VERSION 5.7 ;
  NOWIREEXTENSIONATPIN ON ;
  DIVIDERCHAR "/" ;
  BUSBITCHARS "[]" ;
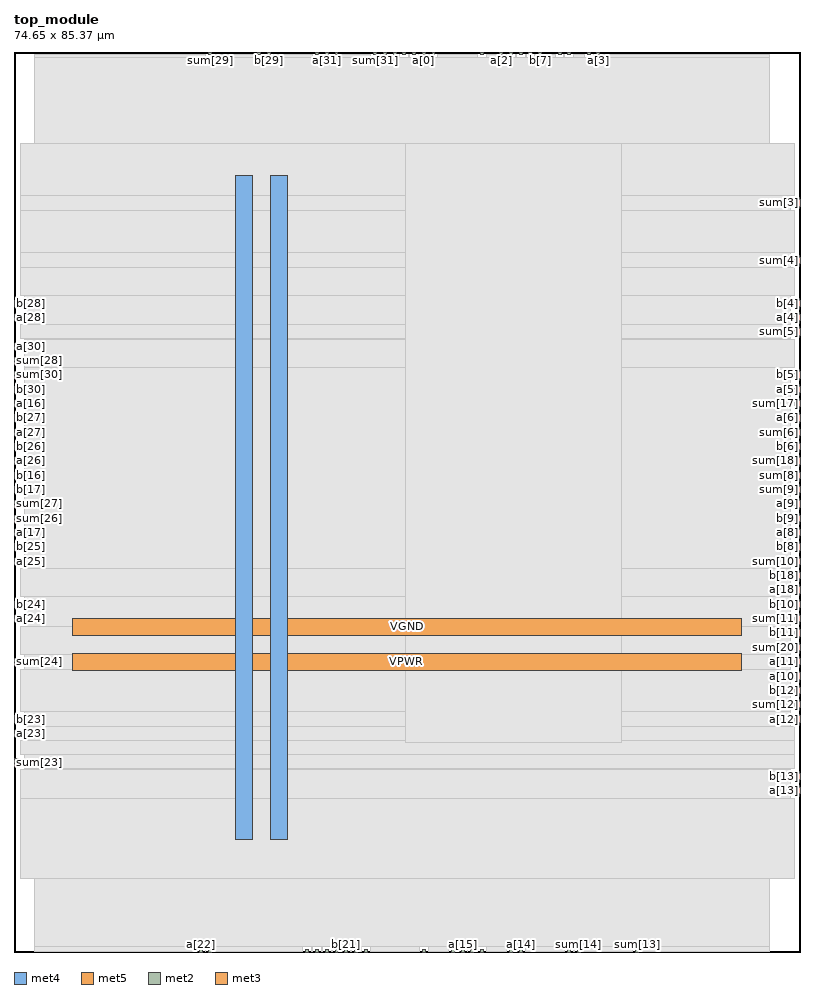
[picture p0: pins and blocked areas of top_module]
MACRO top_module
  CLASS BLOCK ;
  FOREIGN top_module ;
  ORIGIN 0.000 0.000 ;
  SIZE 74.650 BY 85.370 ;
  PIN VGND
    DIRECTION INOUT ;
    USE GROUND ;
    PORT
      LAYER met4 ;
        RECT 24.340 10.640 25.940 73.680 ;
    END
    PORT
      LAYER met5 ;
        RECT 5.520 30.030 69.000 31.630 ;
    END
  END VGND
  PIN VPWR
    DIRECTION INOUT ;
    USE POWER ;
    PORT
      LAYER met4 ;
        RECT 21.040 10.640 22.640 73.680 ;
    END
    PORT
      LAYER met5 ;
        RECT 5.520 26.730 69.000 28.330 ;
    END
  END VPWR
  PIN a[0]
    DIRECTION INPUT ;
    USE SIGNAL ;
    ANTENNAGATEAREA 0.213000 ;
    PORT
      LAYER met2 ;
        RECT 38.730 85.090 39.010 85.370 ;
    END
  END a[0]
  PIN a[10]
    DIRECTION INPUT ;
    USE SIGNAL ;
    ANTENNAGATEAREA 0.213000 ;
    PORT
      LAYER met3 ;
        RECT 74.050 25.880 74.650 26.480 ;
    END
  END a[10]
  PIN a[11]
    DIRECTION INPUT ;
    USE SIGNAL ;
    ANTENNAGATEAREA 0.213000 ;
    PORT
      LAYER met3 ;
        RECT 74.050 27.240 74.650 27.840 ;
    END
  END a[11]
  PIN a[12]
    DIRECTION INPUT ;
    USE SIGNAL ;
    ANTENNAGATEAREA 0.213000 ;
    PORT
      LAYER met3 ;
        RECT 74.050 21.800 74.650 22.400 ;
    END
  END a[12]
  PIN a[13]
    DIRECTION INPUT ;
    USE SIGNAL ;
    ANTENNAGATEAREA 0.213000 ;
    PORT
      LAYER met3 ;
        RECT 74.050 15.000 74.650 15.600 ;
    END
  END a[13]
  PIN a[14]
    DIRECTION INPUT ;
    USE SIGNAL ;
    ANTENNAGATEAREA 0.213000 ;
    PORT
      LAYER met2 ;
        RECT 47.930 0.000 48.210 0.280 ;
    END
  END a[14]
  PIN a[15]
    DIRECTION INPUT ;
    USE SIGNAL ;
    ANTENNAGATEAREA 0.213000 ;
    PORT
      LAYER met2 ;
        RECT 42.410 0.000 42.690 0.280 ;
    END
  END a[15]
  PIN a[16]
    DIRECTION INPUT ;
    USE SIGNAL ;
    ANTENNAGATEAREA 0.213000 ;
    PORT
      LAYER met3 ;
        RECT 0.000 51.720 0.600 52.320 ;
    END
  END a[16]
  PIN a[17]
    DIRECTION INPUT ;
    USE SIGNAL ;
    ANTENNAGATEAREA 0.213000 ;
    PORT
      LAYER met3 ;
        RECT 0.000 39.480 0.600 40.080 ;
    END
  END a[17]
  PIN a[18]
    DIRECTION INPUT ;
    USE SIGNAL ;
    ANTENNAGATEAREA 0.126000 ;
    PORT
      LAYER met3 ;
        RECT 74.050 34.040 74.650 34.640 ;
    END
  END a[18]
  PIN a[19]
    DIRECTION INPUT ;
    USE SIGNAL ;
    ANTENNAGATEAREA 0.213000 ;
    PORT
      LAYER met2 ;
        RECT 32.290 0.000 32.570 0.280 ;
    END
  END a[19]
  PIN a[1]
    DIRECTION INPUT ;
    USE SIGNAL ;
    ANTENNAGATEAREA 0.742500 ;
    PORT
      LAYER met2 ;
        RECT 35.050 85.090 35.330 85.370 ;
    END
  END a[1]
  PIN a[20]
    DIRECTION INPUT ;
    USE SIGNAL ;
    ANTENNAGATEAREA 0.213000 ;
    PORT
      LAYER met2 ;
        RECT 44.250 0.000 44.530 0.280 ;
    END
  END a[20]
  PIN a[21]
    DIRECTION INPUT ;
    USE SIGNAL ;
    ANTENNAGATEAREA 0.213000 ;
    PORT
      LAYER met2 ;
        RECT 30.450 0.000 30.730 0.280 ;
    END
  END a[21]
  PIN a[22]
    DIRECTION INPUT ;
    USE SIGNAL ;
    ANTENNAGATEAREA 0.213000 ;
    PORT
      LAYER met2 ;
        RECT 17.570 0.000 17.850 0.280 ;
    END
  END a[22]
  PIN a[23]
    DIRECTION INPUT ;
    USE SIGNAL ;
    ANTENNAGATEAREA 0.213000 ;
    PORT
      LAYER met3 ;
        RECT 0.000 20.440 0.600 21.040 ;
    END
  END a[23]
  PIN a[24]
    DIRECTION INPUT ;
    USE SIGNAL ;
    ANTENNAGATEAREA 0.213000 ;
    PORT
      LAYER met3 ;
        RECT 0.000 31.320 0.600 31.920 ;
    END
  END a[24]
  PIN a[25]
    DIRECTION INPUT ;
    USE SIGNAL ;
    ANTENNAGATEAREA 0.213000 ;
    PORT
      LAYER met3 ;
        RECT 0.000 36.760 0.600 37.360 ;
    END
  END a[25]
  PIN a[26]
    DIRECTION INPUT ;
    USE SIGNAL ;
    ANTENNAGATEAREA 0.213000 ;
    PORT
      LAYER met3 ;
        RECT 0.000 46.280 0.600 46.880 ;
    END
  END a[26]
  PIN a[27]
    DIRECTION INPUT ;
    USE SIGNAL ;
    ANTENNAGATEAREA 0.213000 ;
    PORT
      LAYER met3 ;
        RECT 0.000 49.000 0.600 49.600 ;
    END
  END a[27]
  PIN a[28]
    DIRECTION INPUT ;
    USE SIGNAL ;
    ANTENNAGATEAREA 0.213000 ;
    PORT
      LAYER met3 ;
        RECT 0.000 59.880 0.600 60.480 ;
    END
  END a[28]
  PIN a[29]
    DIRECTION INPUT ;
    USE SIGNAL ;
    ANTENNAGATEAREA 0.213000 ;
    PORT
      LAYER met2 ;
        RECT 23.090 85.090 23.370 85.370 ;
    END
  END a[29]
  PIN a[2]
    DIRECTION INPUT ;
    USE SIGNAL ;
    ANTENNAGATEAREA 0.213000 ;
    PORT
      LAYER met2 ;
        RECT 46.090 85.090 46.370 85.370 ;
    END
  END a[2]
  PIN a[30]
    DIRECTION INPUT ;
    USE SIGNAL ;
    ANTENNAGATEAREA 0.213000 ;
    PORT
      LAYER met3 ;
        RECT 0.000 57.160 0.600 57.760 ;
    END
  END a[30]
  PIN a[31]
    DIRECTION INPUT ;
    USE SIGNAL ;
    ANTENNAGATEAREA 0.213000 ;
    PORT
      LAYER met2 ;
        RECT 29.530 85.090 29.810 85.370 ;
    END
  END a[31]
  PIN a[3]
    DIRECTION INPUT ;
    USE SIGNAL ;
    ANTENNAGATEAREA 0.213000 ;
    PORT
      LAYER met2 ;
        RECT 55.290 85.090 55.570 85.370 ;
    END
  END a[3]
  PIN a[4]
    DIRECTION INPUT ;
    USE SIGNAL ;
    ANTENNAGATEAREA 0.213000 ;
    PORT
      LAYER met3 ;
        RECT 74.050 59.880 74.650 60.480 ;
    END
  END a[4]
  PIN a[5]
    DIRECTION INPUT ;
    USE SIGNAL ;
    ANTENNAGATEAREA 0.213000 ;
    PORT
      LAYER met3 ;
        RECT 74.050 53.080 74.650 53.680 ;
    END
  END a[5]
  PIN a[6]
    DIRECTION INPUT ;
    USE SIGNAL ;
    ANTENNAGATEAREA 0.213000 ;
    PORT
      LAYER met3 ;
        RECT 74.050 50.360 74.650 50.960 ;
    END
  END a[6]
  PIN a[7]
    DIRECTION INPUT ;
    USE SIGNAL ;
    ANTENNAGATEAREA 0.213000 ;
    PORT
      LAYER met2 ;
        RECT 48.850 85.090 49.130 85.370 ;
    END
  END a[7]
  PIN a[8]
    DIRECTION INPUT ;
    USE SIGNAL ;
    ANTENNAGATEAREA 0.213000 ;
    PORT
      LAYER met3 ;
        RECT 74.050 39.480 74.650 40.080 ;
    END
  END a[8]
  PIN a[9]
    DIRECTION INPUT ;
    USE SIGNAL ;
    ANTENNAGATEAREA 0.213000 ;
    PORT
      LAYER met3 ;
        RECT 74.050 42.200 74.650 42.800 ;
    END
  END a[9]
  PIN b[0]
    DIRECTION INPUT ;
    USE SIGNAL ;
    ANTENNAGATEAREA 0.495000 ;
    PORT
      LAYER met2 ;
        RECT 36.890 85.090 37.170 85.370 ;
    END
  END b[0]
  PIN b[10]
    DIRECTION INPUT ;
    USE SIGNAL ;
    ANTENNAGATEAREA 0.213000 ;
    PORT
      LAYER met3 ;
        RECT 74.050 32.680 74.650 33.280 ;
    END
  END b[10]
  PIN b[11]
    DIRECTION INPUT ;
    USE SIGNAL ;
    ANTENNAGATEAREA 0.213000 ;
    PORT
      LAYER met3 ;
        RECT 74.050 29.960 74.650 30.560 ;
    END
  END b[11]
  PIN b[12]
    DIRECTION INPUT ;
    USE SIGNAL ;
    ANTENNAGATEAREA 0.213000 ;
    PORT
      LAYER met3 ;
        RECT 74.050 24.520 74.650 25.120 ;
    END
  END b[12]
  PIN b[13]
    DIRECTION INPUT ;
    USE SIGNAL ;
    ANTENNAGATEAREA 0.213000 ;
    PORT
      LAYER met3 ;
        RECT 74.050 16.360 74.650 16.960 ;
    END
  END b[13]
  PIN b[14]
    DIRECTION INPUT ;
    USE SIGNAL ;
    ANTENNAGATEAREA 0.213000 ;
    PORT
      LAYER met2 ;
        RECT 47.010 0.000 47.290 0.280 ;
    END
  END b[14]
  PIN b[15]
    DIRECTION INPUT ;
    USE SIGNAL ;
    ANTENNAGATEAREA 0.213000 ;
    PORT
      LAYER met2 ;
        RECT 41.490 0.000 41.770 0.280 ;
    END
  END b[15]
  PIN b[16]
    DIRECTION INPUT ;
    USE SIGNAL ;
    ANTENNAGATEAREA 0.213000 ;
    PORT
      LAYER met3 ;
        RECT 0.000 44.920 0.600 45.520 ;
    END
  END b[16]
  PIN b[17]
    DIRECTION INPUT ;
    USE SIGNAL ;
    ANTENNAGATEAREA 0.213000 ;
    PORT
      LAYER met3 ;
        RECT 0.000 43.560 0.600 44.160 ;
    END
  END b[17]
  PIN b[18]
    DIRECTION INPUT ;
    USE SIGNAL ;
    ANTENNAGATEAREA 0.126000 ;
    PORT
      LAYER met3 ;
        RECT 74.050 35.400 74.650 36.000 ;
    END
  END b[18]
  PIN b[19]
    DIRECTION INPUT ;
    USE SIGNAL ;
    ANTENNAGATEAREA 0.213000 ;
    PORT
      LAYER met2 ;
        RECT 33.210 0.000 33.490 0.280 ;
    END
  END b[19]
  PIN b[1]
    DIRECTION INPUT ;
    USE SIGNAL ;
    ANTENNAGATEAREA 0.495000 ;
    PORT
      LAYER met2 ;
        RECT 35.970 85.090 36.250 85.370 ;
    END
  END b[1]
  PIN b[20]
    DIRECTION INPUT ;
    USE SIGNAL ;
    ANTENNAGATEAREA 0.213000 ;
    PORT
      LAYER met2 ;
        RECT 43.330 0.000 43.610 0.280 ;
    END
  END b[20]
  PIN b[21]
    DIRECTION INPUT ;
    USE SIGNAL ;
    ANTENNAGATEAREA 0.213000 ;
    PORT
      LAYER met2 ;
        RECT 31.370 0.000 31.650 0.280 ;
    END
  END b[21]
  PIN b[22]
    DIRECTION INPUT ;
    USE SIGNAL ;
    ANTENNAGATEAREA 0.213000 ;
    PORT
      LAYER met2 ;
        RECT 18.490 0.000 18.770 0.280 ;
    END
  END b[22]
  PIN b[23]
    DIRECTION INPUT ;
    USE SIGNAL ;
    ANTENNAGATEAREA 0.213000 ;
    PORT
      LAYER met3 ;
        RECT 0.000 21.800 0.600 22.400 ;
    END
  END b[23]
  PIN b[24]
    DIRECTION INPUT ;
    USE SIGNAL ;
    ANTENNAGATEAREA 0.213000 ;
    PORT
      LAYER met3 ;
        RECT 0.000 32.680 0.600 33.280 ;
    END
  END b[24]
  PIN b[25]
    DIRECTION INPUT ;
    USE SIGNAL ;
    ANTENNAGATEAREA 0.213000 ;
    PORT
      LAYER met3 ;
        RECT 0.000 38.120 0.600 38.720 ;
    END
  END b[25]
  PIN b[26]
    DIRECTION INPUT ;
    USE SIGNAL ;
    ANTENNAGATEAREA 0.213000 ;
    PORT
      LAYER met3 ;
        RECT 0.000 47.640 0.600 48.240 ;
    END
  END b[26]
  PIN b[27]
    DIRECTION INPUT ;
    USE SIGNAL ;
    ANTENNAGATEAREA 0.213000 ;
    PORT
      LAYER met3 ;
        RECT 0.000 50.360 0.600 50.960 ;
    END
  END b[27]
  PIN b[28]
    DIRECTION INPUT ;
    USE SIGNAL ;
    ANTENNAGATEAREA 0.213000 ;
    PORT
      LAYER met3 ;
        RECT 0.000 61.240 0.600 61.840 ;
    END
  END b[28]
  PIN b[29]
    DIRECTION INPUT ;
    USE SIGNAL ;
    ANTENNAGATEAREA 0.213000 ;
    PORT
      LAYER met2 ;
        RECT 24.010 85.090 24.290 85.370 ;
    END
  END b[29]
  PIN b[2]
    DIRECTION INPUT ;
    USE SIGNAL ;
    ANTENNAGATEAREA 0.213000 ;
    PORT
      LAYER met2 ;
        RECT 47.010 85.090 47.290 85.370 ;
    END
  END b[2]
  PIN b[30]
    DIRECTION INPUT ;
    USE SIGNAL ;
    ANTENNAGATEAREA 0.213000 ;
    PORT
      LAYER met3 ;
        RECT 0.000 53.080 0.600 53.680 ;
    END
  END b[30]
  PIN b[31]
    DIRECTION INPUT ;
    USE SIGNAL ;
    ANTENNAGATEAREA 0.213000 ;
    PORT
      LAYER met2 ;
        RECT 30.450 85.090 30.730 85.370 ;
    END
  END b[31]
  PIN b[3]
    DIRECTION INPUT ;
    USE SIGNAL ;
    ANTENNAGATEAREA 0.213000 ;
    PORT
      LAYER met2 ;
        RECT 54.370 85.090 54.650 85.370 ;
    END
  END b[3]
  PIN b[4]
    DIRECTION INPUT ;
    USE SIGNAL ;
    ANTENNAGATEAREA 0.213000 ;
    PORT
      LAYER met3 ;
        RECT 74.050 61.240 74.650 61.840 ;
    END
  END b[4]
  PIN b[5]
    DIRECTION INPUT ;
    USE SIGNAL ;
    ANTENNAGATEAREA 0.213000 ;
    PORT
      LAYER met3 ;
        RECT 74.050 54.440 74.650 55.040 ;
    END
  END b[5]
  PIN b[6]
    DIRECTION INPUT ;
    USE SIGNAL ;
    ANTENNAGATEAREA 0.213000 ;
    PORT
      LAYER met3 ;
        RECT 74.050 47.640 74.650 48.240 ;
    END
  END b[6]
  PIN b[7]
    DIRECTION INPUT ;
    USE SIGNAL ;
    ANTENNAGATEAREA 0.213000 ;
    PORT
      LAYER met2 ;
        RECT 49.770 85.090 50.050 85.370 ;
    END
  END b[7]
  PIN b[8]
    DIRECTION INPUT ;
    USE SIGNAL ;
    ANTENNAGATEAREA 0.213000 ;
    PORT
      LAYER met3 ;
        RECT 74.050 38.120 74.650 38.720 ;
    END
  END b[8]
  PIN b[9]
    DIRECTION INPUT ;
    USE SIGNAL ;
    ANTENNAGATEAREA 0.213000 ;
    PORT
      LAYER met3 ;
        RECT 74.050 40.840 74.650 41.440 ;
    END
  END b[9]
  PIN cin
    DIRECTION INPUT ;
    USE SIGNAL ;
    ANTENNAGATEAREA 0.742500 ;
    PORT
      LAYER met2 ;
        RECT 37.810 85.090 38.090 85.370 ;
    END
  END cin
  PIN cout
    DIRECTION OUTPUT ;
    USE SIGNAL ;
    ANTENNADIFFAREA 1.336500 ;
    PORT
      LAYER met2 ;
        RECT 28.610 85.090 28.890 85.370 ;
    END
  END cout
  PIN sum[0]
    DIRECTION OUTPUT ;
    USE SIGNAL ;
    ANTENNADIFFAREA 1.782000 ;
    PORT
      LAYER met2 ;
        RECT 44.250 85.090 44.530 85.370 ;
    END
  END sum[0]
  PIN sum[10]
    DIRECTION OUTPUT ;
    USE SIGNAL ;
    ANTENNADIFFAREA 0.891000 ;
    PORT
      LAYER met3 ;
        RECT 74.050 36.760 74.650 37.360 ;
    END
  END sum[10]
  PIN sum[11]
    DIRECTION OUTPUT ;
    USE SIGNAL ;
    ANTENNADIFFAREA 1.336500 ;
    PORT
      LAYER met3 ;
        RECT 74.050 31.320 74.650 31.920 ;
    END
  END sum[11]
  PIN sum[12]
    DIRECTION OUTPUT ;
    USE SIGNAL ;
    ANTENNADIFFAREA 0.891000 ;
    PORT
      LAYER met3 ;
        RECT 74.050 23.160 74.650 23.760 ;
    END
  END sum[12]
  PIN sum[13]
    DIRECTION OUTPUT ;
    USE SIGNAL ;
    ANTENNADIFFAREA 1.336500 ;
    PORT
      LAYER met2 ;
        RECT 58.970 0.000 59.250 0.280 ;
    END
  END sum[13]
  PIN sum[14]
    DIRECTION OUTPUT ;
    USE SIGNAL ;
    ANTENNADIFFAREA 1.782000 ;
    PORT
      LAYER met2 ;
        RECT 53.450 0.000 53.730 0.280 ;
    END
  END sum[14]
  PIN sum[15]
    DIRECTION OUTPUT ;
    USE SIGNAL ;
    ANTENNADIFFAREA 1.782000 ;
    PORT
      LAYER met2 ;
        RECT 52.530 0.000 52.810 0.280 ;
    END
  END sum[15]
  PIN sum[16]
    DIRECTION OUTPUT ;
    USE SIGNAL ;
    ANTENNADIFFAREA 1.336500 ;
    PORT
      LAYER met2 ;
        RECT 39.650 85.090 39.930 85.370 ;
    END
  END sum[16]
  PIN sum[17]
    DIRECTION OUTPUT ;
    USE SIGNAL ;
    ANTENNADIFFAREA 1.336500 ;
    PORT
      LAYER met3 ;
        RECT 74.050 51.720 74.650 52.320 ;
    END
  END sum[17]
  PIN sum[18]
    DIRECTION OUTPUT ;
    USE SIGNAL ;
    ANTENNADIFFAREA 1.336500 ;
    PORT
      LAYER met3 ;
        RECT 74.050 46.280 74.650 46.880 ;
    END
  END sum[18]
  PIN sum[19]
    DIRECTION OUTPUT ;
    USE SIGNAL ;
    ANTENNADIFFAREA 1.336500 ;
    PORT
      LAYER met2 ;
        RECT 29.530 0.000 29.810 0.280 ;
    END
  END sum[19]
  PIN sum[1]
    DIRECTION OUTPUT ;
    USE SIGNAL ;
    ANTENNADIFFAREA 1.782000 ;
    PORT
      LAYER met2 ;
        RECT 47.930 85.090 48.210 85.370 ;
    END
  END sum[1]
  PIN sum[20]
    DIRECTION OUTPUT ;
    USE SIGNAL ;
    ANTENNADIFFAREA 1.336500 ;
    PORT
      LAYER met3 ;
        RECT 74.050 28.600 74.650 29.200 ;
    END
  END sum[20]
  PIN sum[21]
    DIRECTION OUTPUT ;
    USE SIGNAL ;
    ANTENNADIFFAREA 1.336500 ;
    PORT
      LAYER met2 ;
        RECT 38.730 0.000 39.010 0.280 ;
    END
  END sum[21]
  PIN sum[22]
    DIRECTION OUTPUT ;
    USE SIGNAL ;
    ANTENNADIFFAREA 1.336500 ;
    PORT
      LAYER met2 ;
        RECT 28.610 0.000 28.890 0.280 ;
    END
  END sum[22]
  PIN sum[23]
    DIRECTION OUTPUT ;
    USE SIGNAL ;
    ANTENNADIFFAREA 1.336500 ;
    PORT
      LAYER met3 ;
        RECT 0.000 17.720 0.600 18.320 ;
    END
  END sum[23]
  PIN sum[24]
    DIRECTION OUTPUT ;
    USE SIGNAL ;
    ANTENNADIFFAREA 1.336500 ;
    PORT
      LAYER met3 ;
        RECT 0.000 27.240 0.600 27.840 ;
    END
  END sum[24]
  PIN sum[25]
    DIRECTION OUTPUT ;
    USE SIGNAL ;
    ANTENNADIFFAREA 1.336500 ;
    PORT
      LAYER met2 ;
        RECT 27.690 0.000 27.970 0.280 ;
    END
  END sum[25]
  PIN sum[26]
    DIRECTION OUTPUT ;
    USE SIGNAL ;
    ANTENNADIFFAREA 1.336500 ;
    PORT
      LAYER met3 ;
        RECT 0.000 40.840 0.600 41.440 ;
    END
  END sum[26]
  PIN sum[27]
    DIRECTION OUTPUT ;
    USE SIGNAL ;
    ANTENNADIFFAREA 1.336500 ;
    PORT
      LAYER met3 ;
        RECT 0.000 42.200 0.600 42.800 ;
    END
  END sum[27]
  PIN sum[28]
    DIRECTION OUTPUT ;
    USE SIGNAL ;
    ANTENNADIFFAREA 1.336500 ;
    PORT
      LAYER met3 ;
        RECT 0.000 55.800 0.600 56.400 ;
    END
  END sum[28]
  PIN sum[29]
    DIRECTION OUTPUT ;
    USE SIGNAL ;
    ANTENNADIFFAREA 1.336500 ;
    PORT
      LAYER met2 ;
        RECT 18.490 85.090 18.770 85.370 ;
    END
  END sum[29]
  PIN sum[2]
    DIRECTION OUTPUT ;
    USE SIGNAL ;
    ANTENNADIFFAREA 1.782000 ;
    PORT
      LAYER met2 ;
        RECT 52.530 85.090 52.810 85.370 ;
    END
  END sum[2]
  PIN sum[30]
    DIRECTION OUTPUT ;
    USE SIGNAL ;
    ANTENNADIFFAREA 1.336500 ;
    PORT
      LAYER met3 ;
        RECT 0.000 54.440 0.600 55.040 ;
    END
  END sum[30]
  PIN sum[31]
    DIRECTION OUTPUT ;
    USE SIGNAL ;
    ANTENNADIFFAREA 1.336500 ;
    PORT
      LAYER met2 ;
        RECT 34.130 85.090 34.410 85.370 ;
    END
  END sum[31]
  PIN sum[3]
    DIRECTION OUTPUT ;
    USE SIGNAL ;
    ANTENNADIFFAREA 0.891000 ;
    PORT
      LAYER met3 ;
        RECT 74.050 70.760 74.650 71.360 ;
    END
  END sum[3]
  PIN sum[4]
    DIRECTION OUTPUT ;
    USE SIGNAL ;
    ANTENNADIFFAREA 0.891000 ;
    PORT
      LAYER met3 ;
        RECT 74.050 65.320 74.650 65.920 ;
    END
  END sum[4]
  PIN sum[5]
    DIRECTION OUTPUT ;
    USE SIGNAL ;
    ANTENNADIFFAREA 1.782000 ;
    PORT
      LAYER met3 ;
        RECT 74.050 58.520 74.650 59.120 ;
    END
  END sum[5]
  PIN sum[6]
    DIRECTION OUTPUT ;
    USE SIGNAL ;
    ANTENNADIFFAREA 1.782000 ;
    PORT
      LAYER met3 ;
        RECT 74.050 49.000 74.650 49.600 ;
    END
  END sum[6]
  PIN sum[7]
    DIRECTION OUTPUT ;
    USE SIGNAL ;
    ANTENNADIFFAREA 1.782000 ;
    PORT
      LAYER met2 ;
        RECT 51.610 85.090 51.890 85.370 ;
    END
  END sum[7]
  PIN sum[8]
    DIRECTION OUTPUT ;
    USE SIGNAL ;
    ANTENNADIFFAREA 0.891000 ;
    PORT
      LAYER met3 ;
        RECT 74.050 44.920 74.650 45.520 ;
    END
  END sum[8]
  PIN sum[9]
    DIRECTION OUTPUT ;
    USE SIGNAL ;
    ANTENNADIFFAREA 0.891000 ;
    PORT
      LAYER met3 ;
        RECT 74.050 43.560 74.650 44.160 ;
    END
  END sum[9]
  OBS
      LAYER nwell ;
        RECT 5.330 10.795 69.190 73.630 ;
      LAYER li1 ;
        RECT 5.520 10.795 69.000 73.525 ;
      LAYER met1 ;
        RECT 1.910 10.640 71.690 76.120 ;
      LAYER met2 ;
        RECT 1.930 84.810 18.210 85.090 ;
        RECT 19.050 84.810 22.810 85.090 ;
        RECT 23.650 84.810 23.730 85.090 ;
        RECT 24.570 84.810 28.330 85.090 ;
        RECT 29.170 84.810 29.250 85.090 ;
        RECT 30.090 84.810 30.170 85.090 ;
        RECT 31.010 84.810 33.850 85.090 ;
        RECT 34.690 84.810 34.770 85.090 ;
        RECT 35.610 84.810 35.690 85.090 ;
        RECT 36.530 84.810 36.610 85.090 ;
        RECT 37.450 84.810 37.530 85.090 ;
        RECT 38.370 84.810 38.450 85.090 ;
        RECT 39.290 84.810 39.370 85.090 ;
        RECT 40.210 84.810 43.970 85.090 ;
        RECT 44.810 84.810 45.810 85.090 ;
        RECT 46.650 84.810 46.730 85.090 ;
        RECT 47.570 84.810 47.650 85.090 ;
        RECT 48.490 84.810 48.570 85.090 ;
        RECT 49.410 84.810 49.490 85.090 ;
        RECT 50.330 84.810 51.330 85.090 ;
        RECT 52.170 84.810 52.250 85.090 ;
        RECT 53.090 84.810 54.090 85.090 ;
        RECT 54.930 84.810 55.010 85.090 ;
        RECT 55.850 84.810 71.670 85.090 ;
        RECT 1.930 0.560 71.670 84.810 ;
        RECT 1.930 0.070 17.290 0.560 ;
        RECT 18.130 0.070 18.210 0.560 ;
        RECT 19.050 0.070 27.410 0.560 ;
        RECT 28.250 0.070 28.330 0.560 ;
        RECT 29.170 0.070 29.250 0.560 ;
        RECT 30.090 0.070 30.170 0.560 ;
        RECT 31.010 0.070 31.090 0.560 ;
        RECT 31.930 0.070 32.010 0.560 ;
        RECT 32.850 0.070 32.930 0.560 ;
        RECT 33.770 0.070 38.450 0.560 ;
        RECT 39.290 0.070 41.210 0.560 ;
        RECT 42.050 0.070 42.130 0.560 ;
        RECT 42.970 0.070 43.050 0.560 ;
        RECT 43.890 0.070 43.970 0.560 ;
        RECT 44.810 0.070 46.730 0.560 ;
        RECT 47.570 0.070 47.650 0.560 ;
        RECT 48.490 0.070 52.250 0.560 ;
        RECT 53.090 0.070 53.170 0.560 ;
        RECT 54.010 0.070 58.690 0.560 ;
        RECT 59.530 0.070 71.670 0.560 ;
      LAYER met3 ;
        RECT 0.600 71.760 74.050 76.665 ;
        RECT 0.600 70.360 73.650 71.760 ;
        RECT 0.600 66.320 74.050 70.360 ;
        RECT 0.600 64.920 73.650 66.320 ;
        RECT 0.600 62.240 74.050 64.920 ;
        RECT 1.000 59.480 73.650 62.240 ;
        RECT 0.600 58.160 73.650 59.480 ;
        RECT 1.000 58.120 73.650 58.160 ;
        RECT 1.000 55.440 74.050 58.120 ;
        RECT 1.000 36.360 73.650 55.440 ;
        RECT 0.600 33.680 73.650 36.360 ;
        RECT 1.000 30.920 73.650 33.680 ;
        RECT 0.600 28.240 73.650 30.920 ;
        RECT 1.000 26.840 73.650 28.240 ;
        RECT 0.600 22.800 73.650 26.840 ;
        RECT 1.000 21.400 73.650 22.800 ;
        RECT 1.000 20.040 74.050 21.400 ;
        RECT 0.600 18.720 74.050 20.040 ;
        RECT 1.000 17.360 74.050 18.720 ;
        RECT 1.000 17.320 73.650 17.360 ;
        RECT 0.600 14.600 73.650 17.320 ;
        RECT 0.600 6.975 74.050 14.600 ;
      LAYER met4 ;
        RECT 37.095 19.895 57.665 76.665 ;
  END
END top_module
END LIBRARY

